VERSION 5.8 ;
DIVIDERCHAR "/" ;
BUSBITCHARS "[]" ;

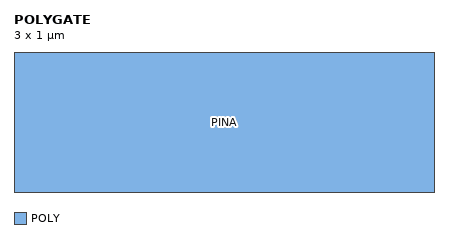
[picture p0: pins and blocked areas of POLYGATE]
MACRO POLYGATE
  CLASS CORE ;
  ORIGIN 0.000 0.000 ;
  SIZE 3.000 BY 1.000 ;
  SYMMETRY X Y ;
  PIN PINA
    DIRECTION INPUT ;
    USE SIGNAL ;
    ANTENNAMODEL OXIDE1 ;
    ANTENNAGATEAREA 1 ;
    PORT
      LAYER POLY ;
        RECT 0.000 0.000 3.000 1.000 ;
    END
  END PINA
END POLYGATE

END LIBRARY
